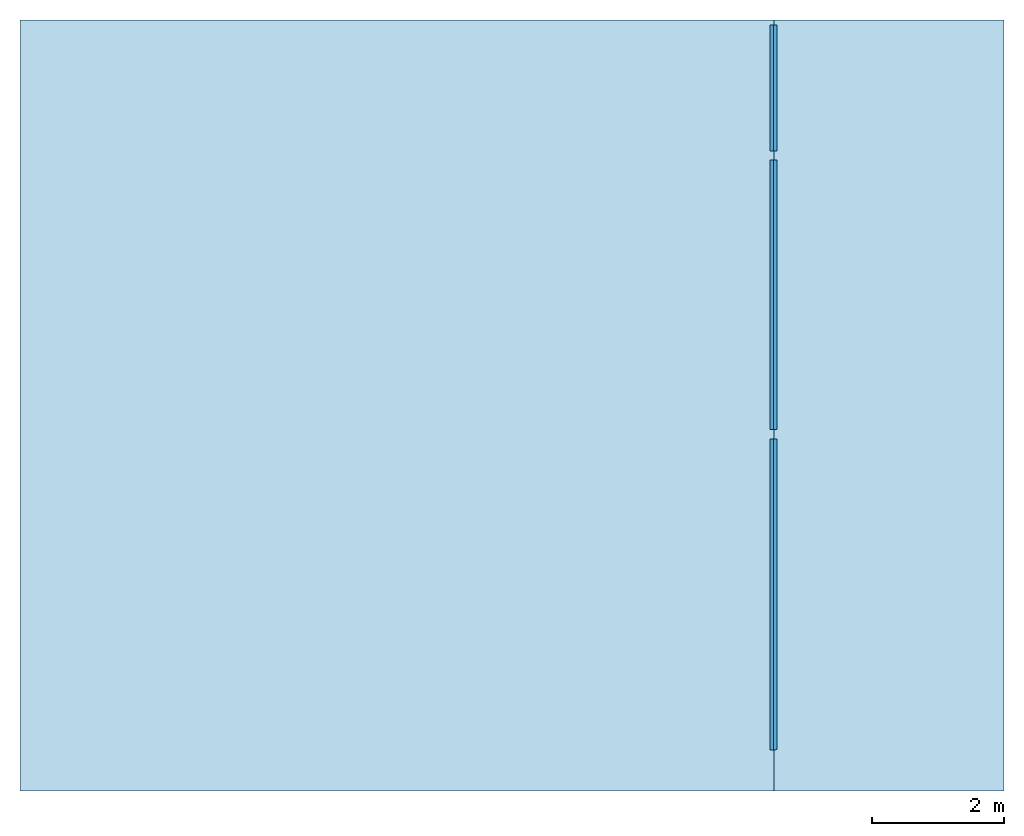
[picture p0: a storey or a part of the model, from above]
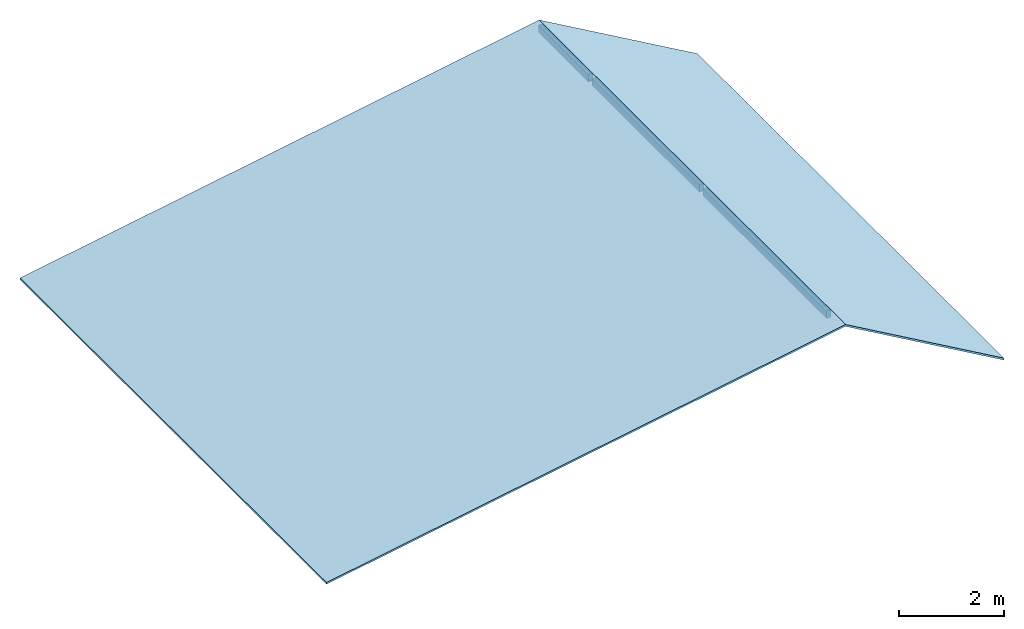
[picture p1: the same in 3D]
Properties of the parts of a building model (IFC4)

# File
Description: ViewDefinition [ReferenceView_V1.2], RevitIdentifiers [ContentGUID: e49f2b07-9c94-4ebe-8864-36e96c9eb5d3, VersionGUID: 72a1a56d-2964-4670-afea-b7860d60a0a9, NumberOfSaves: 74], CoordinateReference [CoordinateBase: Coordonnées partagées], ExchangeRequirement [Structural]
File name: 15-00625-Préfecture des Vosges-PRO-Maquette structure.ifc
Time: 2025-05-12T09:06:08+01:00
Written by: ODA SDAI 24.12
Made in: Autodesk Revit 25.3.0.46 (FRA) - IFC 25.3.0.46

# IfcProject, 15-00625
LongName: Centre d'examen des permis de conduire; Phase: PRO

# IfcSite, Default
RefLatitude: 48, 51, 23, 999633; RefLongitude: 2, 21, 3, 553905; RefElevation: 0 cm
Pset_SiteCommon - Reference: Informations sur le projet

# IfcSite: Regard drain:500 mmx500 mm (5)
Material: <Unnamed>
Pset_SiteCommon - Reference: 500 mmx500 mm
Qto_SiteBaseQuantities - GrossArea: 0.1444 m2
Name (Regard drain:500 mmx500 mm:...)
332220
340264
341394
343831
343919

# IfcBuilding
Pset_BuildingCommon - Reference: Informations sur le projet; NumberOfStoreys: 4
Pset_BuildingElementProxyCommon - Reference: Informations sur le projet; IsExternal: no
Pset_BuildingStoreyCommon - Reference: Informations sur le projet; sets with these values: 2

# IfcBuildingStorey: Niveau:Pointe 8 mm (4)
Pset_BuildingStoreyCommon - Reference: Pointe 8 mm
Name | LongName | Elevation (cm)
Fondation B.O. | Fondation B.O. | -30
± 0.000 | ± 0.000 | 31
+3.00 | +3.00 | 331
+5.25 | +5.25 | 556

# IfcBeam: Poutre - Lamellé-collé:10x10 (11)
In: Fondation B.O.
Type - PredefinedType: BEAM; Material: BM - C24
Type - Pset_BeamCommon - LoadBearing: yes
Pset_BeamCommon - Roll: 0 deg; Reference: 10x10
Pset_EnvironmentalImpactIndicators - Reference: 10x10; sets with these values: 2
Name (Poutre - Lamellé-collé:10x10:...) | IsExternal | Span (cm) | Slope (deg) | NetSurfaceArea (m2) | NetVolume (m3)
253672 | yes | 270.6 | 21.0071 | 1.02658 | 0.0251412
253712 | yes | 459.1 | 12.1585 | 1.83103 | 0.0443514
253883 | yes | 397.4 | 14.4253 | 1.54723 | 0.0376102
256367 | yes | 399.9 | 13.5747 | 1.51601 | 0.036857
257049 | no | 439.6 | 5.91429 | 1.6891 | 0.0415963
258776 | yes | 456.2 | 3.86876 | 1.62873 | 0.0397972
266792 | no | 435.4 | 5.80391 | 1.67125 | 0.0412361
267095 | no | 435.4 | 5.80421 | 1.67169 | 0.0412367
404951 | no | 455 | 2.92662 | 1.77425 | 0.0432159
405012 | no | 400.9 | 3.31704 | 1.54569 | 0.0380108
405029 | no | 403.4 | 3.40332 | 1.56152 | 0.0379228

# IfcBeam: Poutre - Lamellé-collé:10x18 (9)
Type - PredefinedType: BEAM; Material: BLC - GL24h
Type - Pset_BeamCommon - LoadBearing: yes
Pset_BeamCommon - Slope: 0 deg; Roll: 0 deg; Reference: 10x18
Pset_EnvironmentalImpactIndicators - Reference: 10x18; sets with these values: 2
Name (Poutre - Lamellé-collé:10x18:...) | In | IsExternal | Span (cm) | Length (cm) | CrossSectionArea (m2) | OuterSurfaceArea (m2) | GrossSurfaceArea (m2) | NetSurfaceArea (m2) | GrossVolume (m3) | NetVolume (m3)
247824 | Fondation B.O. | yes | 422 | 18 | 0.407954 | 1.50463 | 2.32054 | 2.32054 | 0.0734316 | 0.0734316
248245 | Fondation B.O. | yes | 190.8 | 18 | 0.1906 | 0.72216 | 1.10336 | 1.10336 | 0.034308 | 0.034308
248481 | Fondation B.O. | yes | 466.7 |  |  |  |  | 2.61039 |  | 0.082747
248585 | +5.25 | no | 422 | 407.9 | 0.0170671 | 2.16598 | 2.20012 | 2.20012 | 0.0696168 | 0.0696168
249977 | +5.25 | no | 190.8 | 190.4 | 0.0170671 | 1.01104 | 1.04517 | 1.04517 | 0.0324958 | 0.0324958
250041 | +5.25 | no | 477.4 |  |  |  |  | 2.53231 |  | 0.0802919
251778 | +3.00 | no | 1174.4 |  |  |  |  | 6.33634 |  | 0.196803
252924 | +3.00 | no | 1074.3 |  |  |  |  | 5.61702 |  | 0.165483
268881 | +3.00 | no | 1073.6 | 1073.55 | 0.0166706 | 5.73606 | 5.7694 | 5.7694 | 0.178967 | 0.178967

# IfcBeam: Poutre - Lamellé-collé:10x20 (3)
In: Fondation B.O.
Type - PredefinedType: BEAM; Material: BLC - GL24h
Type - Pset_BeamCommon - LoadBearing: yes
Pset_BeamCommon - IsExternal: no; Roll: 0 deg; Reference: 10x20; Slope: 7.63893 deg
Pset_EnvironmentalImpactIndicators - Reference: 10x20; sets with these values: 2
Qto_BeamBaseQuantities - Length: 10 cm; CrossSectionArea: 0.730739 m2; OuterSurfaceArea: 0.771668 m2; GrossSurfaceArea: 2.23315 m2; NetSurfaceArea: 2.23315 m2; GrossVolume: 0.0730739 m3; NetVolume: 0.0730739 m3
Name (Poutre - Lamellé-collé:10x20:...) | Span (cm)
270714 | 364.3
271733 | 369.4
271742 | 364.3

# IfcBeam: Poutre - Lamellé-collé:14x32 (5)
In: Fondation B.O.
Type - PredefinedType: BEAM; Material: BLC - GL24h
Type - Pset_BeamCommon - LoadBearing: yes
Pset_BeamCommon - IsExternal: yes; Roll: 0 deg; Reference: 14x32
Pset_EnvironmentalImpactIndicators - Reference: 14x32; sets with these values: 2
Qto_BeamBaseQuantities - Length: 14 cm
Name (Poutre - Lamellé-collé:14x32:...) | Span (cm) | Slope (deg) | CrossSectionArea (m2) | OuterSurfaceArea (m2) | GrossSurfaceArea (m2) | NetSurfaceArea (m2) | GrossVolume (m3) = NetVolume (m3)
238878 | 565.4 | 9.94208 | 1.78925 | 1.6687 | 5.24719 | 5.24719 | 0.250495
239277 | 391.5 | 29.8865 | 1.17434 | 1.1546 | 3.50328 | 3.50328 | 0.164407
241186 | 587.3 | 9.94208 | 1.83935 | 1.73201 | 5.41071 | 5.41071 | 0.257509
241188 | 391.5 | 29.8865 | 1.17434 | 1.15464 | 3.50332 | 3.50329 | 0.164407
241289 | 552.8 | 9.94208 | 1.7274 | 1.62076 | 5.07556 | 5.07556 | 0.241836

# IfcBeam: Poutre rectangulaire - Béton:25x25 ht. (2)
In: Fondation B.O.
Type - PredefinedType: BEAM; Material: Béton C20/25
Type - Pset_BeamCommon - LoadBearing: yes
Pset_BeamCommon - IsExternal: no; Reference: 25x25 ht.; Slope: 0 deg; Roll: 0 deg
Pset_EnvironmentalImpactIndicators - Reference: 25x25 ht.; sets with these values: 2
Qto_BeamBaseQuantities - CrossSectionArea: 0.0625 m2
Name (Poutre rectangulaire - Béton:25x25 ht.:...) | Span (cm) | Length (cm) | OuterSurfaceArea (m2) | GrossSurfaceArea (m2) = NetSurfaceArea (m2) | GrossVolume (m3) | NetVolume (m3)
209318 | 372.5 | 326 | 3.26 | 3.385 | 0.20375 | 0.20375
210656 | 567 | 520.5 | 5.205 | 5.33 | 0.325313 | 0.325312

# IfcBuildingElementPart (49)
Name | In | Material
Béton C20/25 | ± 0.000 | Béton C20/25
Isolant rigide | ± 0.000 | Isolant rigide
7 x Isolant rigide | Fondation B.O. | Isolant rigide
7 x Béton, règle sable/ciment | Fondation B.O. | Béton, règle sable/ciment
7 x Béton C20/25 | Fondation B.O. | Béton C20/25
7 x Panneau de grandes particules orientées | ± 0.000 | Panneau de grandes particules orientées
6 x Structure, couche de solives/chevrons en bois d'oeuvre | ± 0.000 | Structure, couche de solives/chevrons en bois d'oeuvre
6 x Panneau de grandes particules orientées | +3.00 | Panneau de grandes particules orientées
6 x Structure, couche de solives/chevrons en bois d'oeuvre | +3.00 | Structure, couche de solives/chevrons en bois d'oeuvre
Structure, couche de solives/chevrons en bois d'oeuvre sans isolant | ± 0.000 | Structure, couche de solives/chevrons en bois d'oeuvre sans isolant

# IfcCableCarrierFitting: Courbure de conduit en plastique rigide - Sans raccords:Raccord TPC BT (14)
In: Fondation B.O.
Type - Material: <Unnamed>
Pset_CableCarrierFittingTypeCommon - Reference: Raccord TPC BT; sets with these values: 2
Name (Courbure de conduit en plastique rigide - Sans raccords:Raccord TPC BT:...)
381655
381657
381707
381709
381749
381759
382104
386991
386993
387013
387017
388068
388160
388214

# IfcCableCarrierFitting: Courbure de conduit en plastique rigide - Sans raccords:Raccord TPC HT (8)
In: Fondation B.O.
Type - Material: <Unnamed>
Pset_CableCarrierFittingTypeCommon - Reference: Raccord TPC HT; sets with these values: 2
Name (Courbure de conduit en plastique rigide - Sans raccords:Raccord TPC HT:...)
387107
387116
387379
387580
387583
387587
387872
387955

# IfcCableCarrierSegment: Conduit sans raccords:TPC (27)
In: Fondation B.O.
Type - PredefinedType: CONDUITSEGMENT
Pset_CableCarrierSegmentTypeCommon - Reference: TPC; sets with these values: 2
Name (Conduit sans raccords:TPC:...) | Length (cm) | CrossSectionArea (m2) | OuterSurfaceArea (m2)
380641 | 52.444 | 0.00153415 | 0.0728229
380750 | 39.379 | 0.0081061 | 0.125692
381237 | 38.4565 | 0.00153415 | 0.0534
381434 | 138.306 | 0.00153415 | 0.19205
381444 | 426.716 | 0.00153415 | 0.592531
381651 | 278.016 | 0.00153415 | 0.386048
381652 | 12.4579 | 0.00153415 | 0.0172989
381662 | 140.699 | 0.00153415 | 0.195372
381697 | 38.4565 | 0.00153415 | 0.0534
381698 | 138.306 | 0.00153415 | 0.19205
381702 | 426.716 | 0.00153415 | 0.592531
381705 | 279.016 | 0.00153415 | 0.387437
381706 | 12.458 | 0.00153415 | 0.017299
381713 | 139.699 | 0.00153415 | 0.193984
381735 | 381.846 | 0.00153415 | 0.530225
381751 | 300.416 | 0.00153415 | 0.417152
381761 | 144.648 | 0.00153415 | 0.200855
382102 | 12.4539 | 0.00153415 | 0.0172933
387097 | 357.894 | 0.0081061 | 1.14235
387110 | 268.887 | 0.0081061 | 0.858251
387119 | 117.717 | 0.0081061 | 0.375738
387377 | 44.3337 | 0.0081061 | 0.141507
387577 | 39.379 | 0.0081061 | 0.125692
387578 | 357.894 | 0.0081061 | 1.14235
387582 | 268.887 | 0.0081061 | 0.858251
387585 | 117.718 | 0.0081061 | 0.375738
387586 | 44.3337 | 0.0081061 | 0.141507

# IfcColumn: Poteau - Bois d'oeuvre:140x140 (6)
In: +3.00
Type - PredefinedType: COLUMN; Material: Bois - Pin
Type - Pset_ColumnCommon - LoadBearing: yes
Qto_ColumnBaseQuantities - Length: 14 cm
Pset_ColumnCommon - IsExternal: no; Reference: 140x140
Pset_EnvironmentalImpactIndicators - Reference: 140x140; sets with these values: 2
Name (Poteau - Bois d'oeuvre:140x140:...) | CrossSectionArea (m2) | OuterSurfaceArea (m2) | GrossVolume (m3) = NetVolume (m3) | Roll (deg) | Slope (deg)
261963 | 0.15881 | 0.381196 | 0.0222334 | 0 | 51.6811
262317 | 0.137019 | 0.328329 | 0.0191826 | 180 | 41.4364
262414 | 0.0883574 | 0.222031 | 0.01237 | 0 | 47.7705
262415 | 0.134314 | 0.320122 | 0.018804 | 180 | 47.7705
272069 | 0.0883574 | 0.222031 | 0.01237 | 0 | 47.7705
272070 | 0.134314 | 0.320122 | 0.018804 | 180 | 47.7705

# IfcColumn: Poteau - Bois d'oeuvre:160x160 (3)
In: ± 0.000
Type - PredefinedType: COLUMN; Material: BM - Douglas
Type - Pset_ColumnCommon - LoadBearing: yes
Qto_ColumnBaseQuantities - Length: 223 cm; CrossSectionArea: 0.0256 m2; OuterSurfaceArea: 1.4272 m2; GrossVolume: 0.057088 m3; NetVolume: 0.057088 m3
Pset_ColumnCommon - IsExternal: no; Reference: 160x160
Pset_EnvironmentalImpactIndicators - Reference: 160x160; sets with these values: 2
Name (Poteau - Bois d'oeuvre:160x160:...)
260961
261099
261378

# IfcColumn: Poteau - Bois d'oeuvre:160x80 (44)
In: ± 0.000
Type - PredefinedType: COLUMN; Material: BM - Douglas
Type - Pset_ColumnCommon - LoadBearing: yes
Qto_ColumnBaseQuantities - CrossSectionArea: 0.0128 m2
Pset_ColumnCommon - IsExternal: no; Reference: 160x80
Pset_EnvironmentalImpactIndicators - Reference: 160x80; sets with these values: 2
Name (Poteau - Bois d'oeuvre:160x80:...) | Length (cm) | OuterSurfaceArea (m2) | GrossVolume (m3) = NetVolume (m3)
273647 | 287 | 1.3776 | 0.036736
274178 | 287 | 1.3776 | 0.036736
274246 | 287 | 1.3776 | 0.036736
274259 | 287 | 1.3776 | 0.036736
274270 | 287 | 1.3776 | 0.036736
274283 | 287 | 1.3776 | 0.036736
274353 | 287 | 1.3776 | 0.036736
274473 | 287 | 1.3776 | 0.036736
274540 | 287 | 1.3776 | 0.036736
274551 | 287 | 1.3776 | 0.036736
274562 | 287 | 1.3776 | 0.036736
274573 | 287 | 1.3776 | 0.036736
274689 | 223 | 1.0704 | 0.028544
275603 | 223 | 1.0704 | 0.028544
275672 | 223 | 1.0704 | 0.028544
275700 | 223 | 1.0704 | 0.028544
275763 | 223 | 1.0704 | 0.028544
275839 | 223 | 1.0704 | 0.028544
275853 | 223 | 1.0704 | 0.028544
275865 | 223 | 1.0704 | 0.028544
275877 | 223 | 1.0704 | 0.028544
275889 | 223 | 1.0704 | 0.028544
275901 | 223 | 1.0704 | 0.028544
275915 | 223 | 1.0704 | 0.028544
275927 | 223 | 1.0704 | 0.028544
275941 | 223 | 1.0704 | 0.028544
275967 | 223 | 1.0704 | 0.028544
275981 | 223 | 1.0704 | 0.028544
275993 | 223 | 1.0704 | 0.028544
276007 | 223 | 1.0704 | 0.028544
276019 | 223 | 1.0704 | 0.028544
276031 | 223 | 1.0704 | 0.028544
276043 | 223 | 1.0704 | 0.028544
276055 | 223 | 1.0704 | 0.028544
276069 | 223 | 1.0704 | 0.028544
276087 | 223 | 1.0704 | 0.028544
276099 | 223 | 1.0704 | 0.028544
276113 | 223 | 1.0704 | 0.028544
276125 | 223 | 1.0704 | 0.028544
276151 | 223 | 1.0704 | 0.028544
276167 | 223 | 1.0704 | 0.028544
276179 | 223 | 1.0704 | 0.028544
276191 | 223 | 1.0704 | 0.028544
276203 | 223 | 1.0704 | 0.028544

# IfcColumn: Poteau - Bois d'oeuvre:200x200 (3)
In: ± 0.000
Type - PredefinedType: COLUMN; Material: BCC - C24
Type - Pset_ColumnCommon - LoadBearing: yes
Qto_ColumnBaseQuantities - CrossSectionArea: 0.04 m2
Pset_ColumnCommon - IsExternal: no; Reference: 200x200
Pset_EnvironmentalImpactIndicators - Reference: 200x200; sets with these values: 2
Name (Poteau - Bois d'oeuvre:200x200:...) | Length (cm) | OuterSurfaceArea (m2) | GrossVolume (m3) = NetVolume (m3)
233240 | 500 | 4 | 0.2
233528 | 412 | 3.296 | 0.1648
233775 | 502 | 4.016 | 0.2008

# IfcDistributionPort (163)
Description: Flow
Name | FlowDirection | PredefinedType | SystemType
OutPort_344095_1 | SOURCE | PIPE | HEATING | Group: Alimentation hydraulique 4
Port_353893_0 | SOURCEANDSINK | PIPE | USERDEFINED | Group: EU/EV
Port_377618_3 | SOURCEANDSINK | PIPE | USERDEFINED | Group: EU/EV
Port_353893_1 | SOURCEANDSINK | PIPE | USERDEFINED | Group: EU/EV
Port_353943_1 | SOURCEANDSINK | PIPE | USERDEFINED | Group: EU/EV
Port_353961_0 | SOURCEANDSINK | PIPE | USERDEFINED | Group: EU/EV
Port_369566_1 | SOURCEANDSINK | PIPE | USERDEFINED | Group: EU/EV
Port_374734_1 | SOURCEANDSINK | PIPE | USERDEFINED | Group: EU/EV
Port_374743_1 | SOURCEANDSINK | PIPE | USERDEFINED | Group: EU/EV
Port_374736_0 | SOURCEANDSINK | PIPE | USERDEFINED | Group: EU/EV
Port_374743_2 | SOURCEANDSINK | PIPE | USERDEFINED | Group: EU/EV
Port_374736_1 | SOURCEANDSINK | PIPE | USERDEFINED | Group: EU/EV
Port_374747_1 | SOURCEANDSINK | PIPE | USERDEFINED | Group: EU/EV
Port_374738_0 | SOURCEANDSINK | PIPE | USERDEFINED | Group: EU/EV
Port_374747_2 | SOURCEANDSINK | PIPE | USERDEFINED | Group: EU/EV
Port_374738_1 | SOURCEANDSINK | PIPE | USERDEFINED | Group: EU/EV
Port_374810_2 | SOURCEANDSINK | PIPE | USERDEFINED | Group: EU/EV
Port_374751_0 | SOURCEANDSINK | PIPE | USERDEFINED | Group: EU/EV
Port_374762_0 | SOURCEANDSINK | PIPE | USERDEFINED | Group: EU/EV
Port_374764_1 | SOURCEANDSINK | PIPE | USERDEFINED | Group: EU/EV
Port_374810_3 | SOURCEANDSINK | PIPE | USERDEFINED | Group: EU/EV
Port_374770_0 | SOURCEANDSINK | PIPE | HEATING | Group: Alimentation hydraulique 10
Port_374770_1 | SOURCEANDSINK | PIPE | HEATING | Group: Alimentation hydraulique 10
Port_374810_1 | SOURCEANDSINK | PIPE | USERDEFINED | Group: EU/EV
Port_377303_1 | SOURCEANDSINK | PIPE | USERDEFINED | Group: EU/EV
Port_375601_0 | SOURCEANDSINK | PIPE | USERDEFINED | Group: EU/EV
Port_377303_0 | SOURCEANDSINK | PIPE | USERDEFINED | Group: EU/EV
Port_377611_2 | SOURCEANDSINK | PIPE | USERDEFINED | Group: EU/EV
Port_377473_0 | SOURCEANDSINK | PIPE | USERDEFINED | Group: EU/EV
Port_377618_2 | SOURCEANDSINK | PIPE | USERDEFINED | Group: EU/EV
Port_377473_1 | SOURCEANDSINK | PIPE | USERDEFINED | Group: EU/EV
Port_377644_2 | SOURCEANDSINK | PIPE | USERDEFINED | Group: EU/EV
Port_377611_1 | SOURCEANDSINK | PIPE | USERDEFINED | Group: EU/EV
Port_378065_0 | SOURCEANDSINK | PIPE | USERDEFINED | Group: EU/EV
Port_377611_3 | SOURCEANDSINK | PIPE | USERDEFINED | Group: EU/EV
Port_377619_0 | SOURCEANDSINK | PIPE | USERDEFINED | Group: EU/EV
Port_377618_1 | SOURCEANDSINK | PIPE | USERDEFINED | Group: EU/EV
Port_377619_1 | SOURCEANDSINK | PIPE | USERDEFINED | Group: EU/EV
Port_377636_0 | SOURCEANDSINK | PIPE | USERDEFINED | Group: EU/EV
Port_377644_1 | SOURCEANDSINK | PIPE | USERDEFINED | Group: EU/EV
Port_377636_1 | SOURCEANDSINK | PIPE | USERDEFINED | Group: EU/EV
Port_377665_1 | SOURCEANDSINK | PIPE | USERDEFINED | Group: EU/EV
Port_377649_1 | SOURCEANDSINK | PIPE | USERDEFINED | Group: EU/EV
Port_377665_2 | SOURCEANDSINK | PIPE | USERDEFINED | Group: EU/EV
Port_378056_0 | SOURCEANDSINK | PIPE | USERDEFINED | Group: EU/EV
Port_378301_2 | SOURCEANDSINK | PIPE | USERDEFINED | Group: EU/EV
Port_378064_1 | SOURCEANDSINK | PIPE | USERDEFINED | Group: EU/EV
Port_378546_0 | SOURCEANDSINK | PIPE | USERDEFINED | Group: EU/EV
Port_378064_2 | SOURCEANDSINK | PIPE | USERDEFINED | Group: EU/EV
Port_378065_1 | SOURCEANDSINK | PIPE | USERDEFINED | Group: EU/EV
Port_378064_3 | SOURCEANDSINK | PIPE | USERDEFINED | Group: EU/EV
Port_378302_0 | SOURCEANDSINK | PIPE | USERDEFINED | Group: EU/EV
Port_378281_1 | SOURCEANDSINK | PIPE | USERDEFINED | Group: EU/EV
Port_378301_3 | SOURCEANDSINK | PIPE | USERDEFINED | Group: EU/EV
Port_378301_1 | SOURCEANDSINK | PIPE | USERDEFINED | Group: EU/EV
Port_378302_1 | SOURCEANDSINK | PIPE | USERDEFINED | Group: EU/EV
Port_378337_1 | SOURCEANDSINK | PIPE | USERDEFINED | Group: EU/EV
Port_378545_3 | SOURCEANDSINK | PIPE | USERDEFINED | Group: EU/EV
Port_378346_0 | SOURCEANDSINK | PIPE | USERDEFINED | Group: EU/EV
Port_378545_1 | SOURCEANDSINK | PIPE | USERDEFINED | Group: EU/EV
Port_378346_1 | SOURCEANDSINK | PIPE | USERDEFINED | Group: EU/EV
Port_378545_2 | SOURCEANDSINK | PIPE | USERDEFINED | Group: EU/EV
Port_378546_1 | SOURCEANDSINK | PIPE | USERDEFINED | Group: EU/EV
Port_379876_0 | SOURCEANDSINK | PIPE | HEATING | Group: AEP
Port_379876_1 | SOURCEANDSINK | PIPE | HEATING | Group: AEP
Port_380641_0 | SOURCEANDSINK | CABLECARRIER | CONVEYING
Port_380641_1 | SOURCEANDSINK | CABLECARRIER | CONVEYING
Port_381749_1 | SOURCEANDSINK | CABLECARRIER | CONVEYING
Port_380750_0 | SOURCEANDSINK | CABLECARRIER | CONVEYING
Port_387107_1 | SOURCEANDSINK | CABLECARRIER | CONVEYING
Port_380750_1 | SOURCEANDSINK | CABLECARRIER | CONVEYING
Port_381237_0 | SOURCEANDSINK | CABLECARRIER | CONVEYING
Port_381237_1 | SOURCEANDSINK | CABLECARRIER | CONVEYING
Port_386993_2 | SOURCEANDSINK | CABLECARRIER | CONVEYING
Port_381434_0 | SOURCEANDSINK | CABLECARRIER | CONVEYING
Port_386991_1 | SOURCEANDSINK | CABLECARRIER | CONVEYING
Port_381434_1 | SOURCEANDSINK | CABLECARRIER | CONVEYING
Port_386993_1 | SOURCEANDSINK | CABLECARRIER | CONVEYING
Port_381444_0 | SOURCEANDSINK | CABLECARRIER | CONVEYING
Port_386991_2 | SOURCEANDSINK | CABLECARRIER | CONVEYING
Port_381444_1 | SOURCEANDSINK | CABLECARRIER | CONVEYING
Port_381655_2 | SOURCEANDSINK | CABLECARRIER | CONVEYING
Port_381651_0 | SOURCEANDSINK | CABLECARRIER | CONVEYING
Port_381655_1 | SOURCEANDSINK | CABLECARRIER | CONVEYING
Port_381651_1 | SOURCEANDSINK | CABLECARRIER | CONVEYING
Port_381657_1 | SOURCEANDSINK | CABLECARRIER | CONVEYING
Port_381652_0 | SOURCEANDSINK | CABLECARRIER | CONVEYING
Port_381657_2 | SOURCEANDSINK | CABLECARRIER | CONVEYING
Port_381652_1 | SOURCEANDSINK | CABLECARRIER | CONVEYING
Port_388214_1 | SOURCEANDSINK | CABLECARRIER | CONVEYING
Port_381662_0 | SOURCEANDSINK | CABLECARRIER | CONVEYING
Port_388214_2 | SOURCEANDSINK | CABLECARRIER | CONVEYING
Port_381662_1 | SOURCEANDSINK | CABLECARRIER | CONVEYING
Port_381697_0 | SOURCEANDSINK | CABLECARRIER | CONVEYING
Port_381697_1 | SOURCEANDSINK | CABLECARRIER | CONVEYING
Port_387017_2 | SOURCEANDSINK | CABLECARRIER | CONVEYING
Port_381698_0 | SOURCEANDSINK | CABLECARRIER | CONVEYING
Port_387013_1 | SOURCEANDSINK | CABLECARRIER | CONVEYING
Port_381698_1 | SOURCEANDSINK | CABLECARRIER | CONVEYING
Port_387017_1 | SOURCEANDSINK | CABLECARRIER | CONVEYING
Port_381702_0 | SOURCEANDSINK | CABLECARRIER | CONVEYING
Port_387013_2 | SOURCEANDSINK | CABLECARRIER | CONVEYING
Port_381702_1 | SOURCEANDSINK | CABLECARRIER | CONVEYING
Port_381707_2 | SOURCEANDSINK | CABLECARRIER | CONVEYING
Port_381705_0 | SOURCEANDSINK | CABLECARRIER | CONVEYING
Port_381707_1 | SOURCEANDSINK | CABLECARRIER | CONVEYING
Port_381705_1 | SOURCEANDSINK | CABLECARRIER | CONVEYING
Port_381709_1 | SOURCEANDSINK | CABLECARRIER | CONVEYING
Port_381706_0 | SOURCEANDSINK | CABLECARRIER | CONVEYING
Port_381709_2 | SOURCEANDSINK | CABLECARRIER | CONVEYING
Port_381706_1 | SOURCEANDSINK | CABLECARRIER | CONVEYING
Port_388160_1 | SOURCEANDSINK | CABLECARRIER | CONVEYING
Port_381713_0 | SOURCEANDSINK | CABLECARRIER | CONVEYING
Port_388160_2 | SOURCEANDSINK | CABLECARRIER | CONVEYING
Port_381713_1 | SOURCEANDSINK | CABLECARRIER | CONVEYING
Port_381735_0 | SOURCEANDSINK | CABLECARRIER | CONVEYING
Port_381749_2 | SOURCEANDSINK | CABLECARRIER | CONVEYING
Port_381735_1 | SOURCEANDSINK | CABLECARRIER | CONVEYING
Port_381759_2 | SOURCEANDSINK | CABLECARRIER | CONVEYING
Port_381751_0 | SOURCEANDSINK | CABLECARRIER | CONVEYING
Port_381759_1 | SOURCEANDSINK | CABLECARRIER | CONVEYING
Port_381751_1 | SOURCEANDSINK | CABLECARRIER | CONVEYING
Port_382104_1 | SOURCEANDSINK | CABLECARRIER | CONVEYING
Port_381761_0 | SOURCEANDSINK | CABLECARRIER | CONVEYING
Port_388068_2 | SOURCEANDSINK | CABLECARRIER | CONVEYING
Port_381761_1 | SOURCEANDSINK | CABLECARRIER | CONVEYING
Port_382102_0 | SOURCEANDSINK | CABLECARRIER | CONVEYING
Port_382104_2 | SOURCEANDSINK | CABLECARRIER | CONVEYING
Port_382102_1 | SOURCEANDSINK | CABLECARRIER | CONVEYING
Port_388068_1 | SOURCEANDSINK | CABLECARRIER | CONVEYING
Port_387097_0 | SOURCEANDSINK | CABLECARRIER | CONVEYING
Port_387107_2 | SOURCEANDSINK | CABLECARRIER | CONVEYING
Port_387097_1 | SOURCEANDSINK | CABLECARRIER | CONVEYING
Port_387116_2 | SOURCEANDSINK | CABLECARRIER | CONVEYING
Port_387110_0 | SOURCEANDSINK | CABLECARRIER | CONVEYING
Port_387116_1 | SOURCEANDSINK | CABLECARRIER | CONVEYING
Port_387110_1 | SOURCEANDSINK | CABLECARRIER | CONVEYING
Port_387379_1 | SOURCEANDSINK | CABLECARRIER | CONVEYING
Port_387119_0 | SOURCEANDSINK | CABLECARRIER | CONVEYING
Port_387955_2 | SOURCEANDSINK | CABLECARRIER | CONVEYING
Port_387119_1 | SOURCEANDSINK | CABLECARRIER | CONVEYING
Port_387377_0 | SOURCEANDSINK | CABLECARRIER | CONVEYING
Port_387379_2 | SOURCEANDSINK | CABLECARRIER | CONVEYING
Port_387377_1 | SOURCEANDSINK | CABLECARRIER | CONVEYING
Port_387955_1 | SOURCEANDSINK | CABLECARRIER | CONVEYING
Port_387577_0 | SOURCEANDSINK | CABLECARRIER | CONVEYING
Port_387580_1 | SOURCEANDSINK | CABLECARRIER | CONVEYING
Port_387577_1 | SOURCEANDSINK | CABLECARRIER | CONVEYING
Port_387578_0 | SOURCEANDSINK | CABLECARRIER | CONVEYING
Port_387580_2 | SOURCEANDSINK | CABLECARRIER | CONVEYING
Port_387578_1 | SOURCEANDSINK | CABLECARRIER | CONVEYING
Port_387583_2 | SOURCEANDSINK | CABLECARRIER | CONVEYING
Port_387582_0 | SOURCEANDSINK | CABLECARRIER | CONVEYING
Port_387583_1 | SOURCEANDSINK | CABLECARRIER | CONVEYING
Port_387582_1 | SOURCEANDSINK | CABLECARRIER | CONVEYING
Port_387587_1 | SOURCEANDSINK | CABLECARRIER | CONVEYING
Port_387585_0 | SOURCEANDSINK | CABLECARRIER | CONVEYING
Port_387872_2 | SOURCEANDSINK | CABLECARRIER | CONVEYING
Port_387585_1 | SOURCEANDSINK | CABLECARRIER | CONVEYING
Port_387586_0 | SOURCEANDSINK | CABLECARRIER | CONVEYING
Port_387587_2 | SOURCEANDSINK | CABLECARRIER | CONVEYING
Port_387586_1 | SOURCEANDSINK | CABLECARRIER | CONVEYING
Port_387872_1 | SOURCEANDSINK | CABLECARRIER | CONVEYING

# IfcDistributionSystem: Alimentation hydraulique (3)
PredefinedType: HEATING
Pset_DistributionSystemCommon - Reference: Alimentation hydraulique
Name
Alimentation hydraulique 4
Alimentation hydraulique 10
AEP

# IfcDistributionSystem: Autre, EU/EV
PredefinedType: USERDEFINED
Pset_DistributionSystemCommon - Reference: Autre

# IfcFooting: Semelle filante:SF 50x25 ht. (6)
In: Fondation B.O.
Type - PredefinedType: STRIP_FOOTING
Material: Béton C20/25
Pset_EnvironmentalImpactIndicators - Reference: SF 50x25 ht.; sets with these values: 4
Qto_FootingBaseQuantities - Length: 25 cm
Name (Semelle filante:SF 50x25 ht.:...) | CrossSectionArea (m2) | OuterSurfaceArea (m2) | GrossSurfaceArea (m2) | GrossVolume (m3) | NetVolume (m3)
198844 | 1.375 | 1.625 | 4.375 | 0.34375 | 0.74625 | Qto_FootingBaseQuantities - Width: 275 cm; Height: 50 cm
206181 | 0.60775 | 0.9575 | 2.173 | 0.151937 | 0.898187 | Qto_FootingBaseQuantities - Width: 322 cm; Height: 50 cm
208354 | 1.882 | 2.17 | 5.934 | 0.4705 | 0.4705
208367 | 5.2325 | 5.4825 | 15.9475 | 1.30812 | 1.30812 | Qto_FootingBaseQuantities - Width: 1046.5 cm; Height: 50 cm
209443 | 1.0025 | 1.455 | 3.46 | 0.250625 | 0.250625
209463 | 0.9525 | 1.405 | 3.31 | 0.238125 | 0.238125

# IfcFooting: Semelle filante:SF 50x25 ht. 2 (7)
In: Fondation B.O.
Type - PredefinedType: STRIP_FOOTING
Material: Béton C20/25
Pset_EnvironmentalImpactIndicators - Reference: SF 50x25 ht. 2; sets with these values: 4
Qto_FootingBaseQuantities - Length: 25 cm
Name (Semelle filante:SF 50x25 ht. 2:...) | Width (cm) | Height (cm) | CrossSectionArea (m2) | OuterSurfaceArea (m2) | GrossSurfaceArea (m2) | GrossVolume (m3) = NetVolume (m3)
198193 | 820 | 50 | 4.1 | 4.35 | 12.55 | 1.025
198208 | 492 | 50 | 2.46 | 2.71 | 7.63 | 0.615
198218 | 363 | 50 | 1.815 | 2.065 | 5.695 | 0.45375
198232 | 163 | 50 | 0.815 | 1.065 | 2.695 | 0.20375
198249 | 960 | 50 | 4.8 | 5.05 | 14.65 | 1.2
198259 | 1399 | 50 | 6.995 | 7.245 | 21.235 | 1.74875
223356 |  |  | 2.58225 | 2.875 | 8.0395 | 0.645563

# IfcMember: Poutre - Lamellé-collé:10x10 (3)
In: Fondation B.O.
Type - PredefinedType: BRACE; Material: BM - C24
Type - Pset_MemberCommon - LoadBearing: yes
Pset_EnvironmentalImpactIndicators - Reference: 10x10
Pset_MemberCommon - Roll: 0 deg; Reference: 10x10
Name (Poutre - Lamellé-collé:10x10:...) | IsExternal | Span (cm) | Slope (deg) | NetSurfaceArea (m2) | NetVolume (m3)
257361 | yes | 400.8 | 4.69304 | 1.41485 | 0.0345599
257390 | yes | 396 | 4.49575 | 1.53956 | 0.0379342
272898 | no | 252.1 | 5.28221 | 0.960764 | 0.0231489

# IfcMember: Poutre - Lamellé-collé:10x18 (16)
In: Fondation B.O.
Type - PredefinedType: PURLIN; Material: BLC - GL24h
Type - Pset_MemberCommon - LoadBearing: yes
Pset_EnvironmentalImpactIndicators - Reference: 10x18
Pset_MemberCommon - Slope: 0 deg; Roll: 0 deg; Reference: 10x18
Name (Poutre - Lamellé-collé:10x18:...) | IsExternal | Span (cm) | Length (cm) | CrossSectionArea (m2) | OuterSurfaceArea (m2) | GrossSurfaceArea (m2) | NetSurfaceArea (m2) | GrossVolume (m3) | NetVolume (m3)
249195 | yes | 422 | 18 | 0.408 | 1.5048 | 2.3208 | 2.3208 | 0.07344 | 0.07344
249285 | yes | 422 | 18 | 0.408 | 1.5048 | 2.3208 | 2.3208 | 0.07344 | 0.07344
249292 | yes | 620.7 | 18 | 0.631394 | 2.30902 | 3.5718 | 3.5718 | 0.113651 | 0.113651
249740 | yes | 190.8 | 18 | 0.1904 | 0.72144 | 1.10224 | 1.10224 | 0.034272 | 0.034272
249853 | yes | 494.5 |  |  |  |  | 2.76816 |  | 0.0878181
249854 | yes | 511.5 |  |  |  |  | 2.86319 |  | 0.0908726
249855 | yes | 528.6 |  |  |  |  | 2.95901 |  | 0.0939526
250751 | yes | 620.7 | 18 | 0.6137 | 2.24532 | 3.47272 | 3.47272 | 0.110466 | 0.110466
251517 | yes | 190.8 | 18 | 0.1904 | 0.72144 | 1.10224 | 1.10224 | 0.034272 | 0.034272
251607 | yes | 541.2 |  |  |  |  | 3.02984 |  | 0.0962293
272228 | no | 181.9 | 18 | 0.183427 | 0.696338 | 1.06319 | 1.06319 | 0.0330169 | 0.0330169
306267 | no | 181.8 | 18 | 0.18345 | 0.69642 | 1.06332 | 1.06332 | 0.033021 | 0.033021
403328 | no | 420 | 18 | 0.409932 | 1.51175 | 2.33162 | 2.33162 | 0.0737877 | 0.0737877
403339 | no | 465.1 | 18 | 0.4601 | 1.69236 | 2.61256 | 2.61256 | 0.082818 | 0.082818
404074 | no | 420 | 18 | 0.41 | 1.512 | 2.332 | 2.332 | 0.0738 | 0.0738
404186 | no | 465.1 | 18 | 0.460017 | 1.69206 | 2.6121 | 2.6121 | 0.0828031 | 0.0828031

# IfcOpeningElement (3)
In: ± 0.000
PredefinedType: OPENING
Qto_OpeningElementBaseQuantities - Depth: 304.8 cm; Height: 222 cm; Width: 102 cm
Name (Mur de base:Relevé 15 cm:...)
196332
196387
196490

# IfcPipeFitting: Plumbing-Bend-Valsir-PP-Negative-02:Standard (4)
In: Fondation B.O.
Type - Material: RAL 7037
Type - Pset_ManufacturerTypeInformation - Manufacturer: Valsir S.p.A.
Pset_EnvironmentalImpactIndicators - Reference: Standard; sets with these values: 2
Group: EU/EV
Name (Plumbing-Bend-Valsir-PP-Negative-02:Standard:...)
374743
374747
377644
377665

# IfcPipeFitting: Plumbing-Branch-Valsir-PP-02:Standard (6)
In: Fondation B.O.
Type - Material: RAL 7037
Type - Pset_ManufacturerTypeInformation - Manufacturer: Valsir S.p.A.
Pset_EnvironmentalImpactIndicators - Reference: Standard; sets with these values: 2
Group: EU/EV
Name (Plumbing-Branch-Valsir-PP-02:Standard:...)
374810
377611
377618
378064
378301
378545

# IfcPipeFitting: ^DON'T_USE^Plumbing-Bend-Valsir-PP-Positive-02_ForDouble45Bend:Standard (12)
In: Fondation B.O.
Type - Material: RAL 7037
Type - Pset_ManufacturerTypeInformation - Manufacturer: Valsir S.p.A.
Pset_EnvironmentalImpactIndicators - Reference: Standard; sets with these values: 2
Name (^DON'T_USE^Plumbing-Bend-Valsir-PP-Positive-02_ForDouble45Bend:Standard:...)
375411
375413
375515
375517
377830
377832
378252
378254
378314
378316
378557
378559

# IfcPipeSegment: Canalisation souple arrondie:PEHD, Canalisation souple arrondie:PEHD:379876
In: Fondation B.O.
Type - PredefinedType: FLEXIBLESEGMENT
Pset_EnvironmentalImpactIndicators - Reference: PEHD; sets with these values: 2
Group: AEP

# IfcPipeSegment: Canalisation:Drain enrobé (5)
In: Fondation B.O.
Pset_EnvironmentalImpactIndicators - Reference: Drain enrobé; sets with these values: 2
Qto_PipeSegmentBaseQuantities - GrossCrossSectionArea: 0.0102593 m2; NetCrossSectionArea: 0.0102593 m2
Name (Canalisation:Drain enrobé:...) | Length (cm) | OuterSurfaceArea (m2)
341244 | 975 | 3.50107
343793 | 1796.5 | 6.45094
344029 | 1024.5 | 3.67882
344061 | 1855.5 | 6.6628
344095 | 100 | 0.359084 | Group: Alimentation hydraulique 4

# IfcPipeSegment: Canalisation:Valsir PP3 (24)
In: Fondation B.O.
Type - Pset_ManufacturerTypeInformation - Manufacturer: Valsir S.p.A.
Pset_EnvironmentalImpactIndicators - Reference: Valsir PP3; sets with these values: 2
Qto_PipeSegmentBaseQuantities - GrossCrossSectionArea: 0.00950189 m2; NetCrossSectionArea: 0.00950189 m2
Name (Canalisation:Valsir PP3:...) | Length (cm) | OuterSurfaceArea (m2) | Group
353893 | 101.827 | 0.351888 | EU/EV
353943 | 95.3738 | 0.329588 | EU/EV
353961 | 48.8721 | 0.16889 | EU/EV
369566 | 88.144 | 0.304604 | EU/EV
374734 | 7.5888 | 0.026225 | EU/EV
374736 | 289.345 | 0.999905 | EU/EV
374738 | 237.158 | 0.819558 | EU/EV
374751 | 96.6627 | 0.334042 | EU/EV
374762 | 93.6453 | 0.323615 | EU/EV
374764 | 162.488 | 0.561519 | EU/EV
374770 | 94.6895 | 0.327224 | Alimentation hydraulique 10
375601 | 91.4242 | 0.315939 | EU/EV
377303 | 30.6884 | 0.106051 | EU/EV
377473 | 49.7103 | 0.171786 | EU/EV
377619 | 171.107 | 0.591305 | EU/EV
377636 | 143.956 | 0.497476 | EU/EV
377649 | 110.295 | 0.381151 | EU/EV
378056 | 107.784 | 0.372474 | EU/EV
378065 | 27.0526 | 0.0934871 | EU/EV
378281 | 60.0539 | 0.207531 | EU/EV
378302 | 38.1827 | 0.13195 | EU/EV
378337 | 36.7693 | 0.127066 | EU/EV
378346 | 389.836 | 1.34718 | EU/EV
378546 | 51.2289 | 0.177034 | EU/EV

# IfcRoof: Toit de base:Bac Acier 3.333.39 T, Toit de base:Bac Acier 3.333.39 T:262438
In: +3.00
Pset_EnvironmentalImpactIndicators - Reference: Bac Acier 3.333.39 T
Pset_RoofCommon - IsExternal: yes; Reference: Bac Acier 3.333.39 T
Qto_RoofBaseQuantities - GrossArea: 43.7491 m2; NetArea: 43.7491 m2; ProjectedArea: 43.3609 m2

# IfcRoof: Toit de base:Bac Acier 3.333.39 T, Toit de base:Bac Acier 3.333.39 T:234167
In: +5.25
Type - Pset_RoofCommon - ThermalTransmittance: 415.385 kg/K/s3
Material: Panneau métallique
Pset_EnvironmentalImpactIndicators - Reference: Bac Acier 3.333.39 T
Pset_RoofCommon - IsExternal: yes; Reference: Bac Acier 3.333.39 T
Qto_RoofBaseQuantities - GrossArea: 182.037 m2; NetArea: 182.037 m2; ProjectedArea: 173.766 m2

# IfcSlab: Gros béton:Gros béton, Gros béton:Gros béton:318225
In: Fondation B.O.
Type - PredefinedType: BASESLAB
Pset_EnvironmentalImpactIndicators - Reference: Gros béton; sets with these values: 2
Pset_SlabCommon - IsExternal: no; Reference: Gros béton
Qto_SlabBaseQuantities - Width: 322 cm; Length: 50 cm; Depth: 10 cm; Perimeter: 744 cm; GrossArea: 1.61 m2; NetArea: 39.2145 m2; GrossVolume: 0.161 m3; NetVolume: 3.92145 m3

# IfcSlab: Semelle Isolée + GB:100x100x30 ht. (4)
In: Fondation B.O.
Type - PredefinedType: BASESLAB; Material: Par défaut
Pset_EnvironmentalImpactIndicators - Reference: 100x100x30 ht.; sets with these values: 2
Pset_SlabCommon - IsExternal: no; Reference: 100x100x30 ht.
Qto_SlabBaseQuantities - Width: 100 cm; Length: 100 cm; Perimeter: 400 cm; GrossArea: 1 m2; NetArea: 2 m2; NetVolume: 0.35 m3
Name (Semelle Isolée + GB:100x100x30 ht.:...) | Depth (cm) | GrossVolume (m3)
206858 | 30 | 0.3
207169 | 5 | 0.05 | Pset_SlabCommon - PitchAngle: 0 deg
207300 | 5 | 0.05 | Pset_SlabCommon - PitchAngle: 0 deg
207585 | 30 | 0.3

# IfcSlab: Sol:Dalle béton 20 cm, Sol:Dalle béton 20 cm:196768
In: ± 0.000
Type - PredefinedType: FLOOR
Type - Pset_SlabCommon - ThermalTransmittance: 0.175 kg/K/s3
Pset_EnvironmentalImpactIndicators - Reference: Dalle béton 20 cm; sets with these values: 2
Pset_SlabCommon - LoadBearing: yes; Reference: Dalle béton 20 cm; PitchAngle: 0 deg; IsExternal: no
Qto_SlabBaseQuantities - Béton C20/25, Width: 20 cm; Isolant rigide, Width: 20 cm; Width: 40 cm; GrossArea: 133.303 m2; NetArea: 133.303 m2; NetVolume: 53.3212 m3

# IfcSlab: Toit de base:Bac Acier 3.333.39 T, Toit de base:Bac Acier 3.333.39 T:262438
In: +3.00
Type - Pset_RoofCommon - ThermalTransmittance: 415.385 kg/K/s3
PredefinedType: ROOF; Material: Panneau métallique
Pset_EnvironmentalImpactIndicators - Reference: Bac Acier 3.333.39 T; sets with these values: 2
Pset_SlabCommon - IsExternal: yes; Reference: Bac Acier 3.333.39 T; PitchAngle: 7.63893 deg
Qto_SlabBaseQuantities - NetArea: 4.06443 m2; NetVolume: 0.158513 m2; GrossArea: 43.7491 m2; GrossVolume: 0.158513 m2; Length: 3.9 cm; Perimeter: 3083.77 cm

# IfcWall: Mur de base:MOB - 145+12 mm (12)
Type - PredefinedType: STANDARD
Type - Pset_WallCommon - ThermalTransmittance: 0.169492 kg/K/s3
Pset_EnvironmentalImpactIndicators - Reference: MOB - 145+12 mm; sets with these values: 2
Pset_WallCommon - IsExternal: yes; LoadBearing: yes; Reference: MOB - 145+12 mm
Name (Mur de base:MOB - 145+12 mm:...) | In | ExtendToStructure | Length (cm) | NetVolume (m3)
228137 | ± 0.000 | no | 893.7 | 3.4645
228414 | ± 0.000 | no | 190 | 0.850155
228561 | ± 0.000 | no | 561 | 2.18191
228720 | ± 0.000 | no | 775.7 | 3.08465
228940 | ± 0.000 | no | 1454.7 | 4.49475
229113 | ± 0.000 | no | 965.7 | 3.92249
235645 | +3.00 | yes | 775.7 | 0.159568
235821 | +3.00 | yes | 1454.7 | 2.79822
236007 | +3.00 | yes | 965.7 | 0.306464
236276 | +3.00 | yes | 893.7 | 2.17487
236447 | +3.00 | yes | 190 | 0.334898
236660 | +3.00 | yes | 561 | 0.654611

# IfcWall: Mur de base:MOB - 145+12 mm sans isolant, Mur de base:MOB - 145+12 mm sans isolant:259256
In: ± 0.000
Type - PredefinedType: STANDARD
Type - Pset_WallCommon - ThermalTransmittance: 0.169492 kg/K/s3
Pset_EnvironmentalImpactIndicators - Reference: MOB - 145+12 mm sans isolant; sets with these values: 2
Pset_WallCommon - IsExternal: yes; LoadBearing: yes; ExtendToStructure: no; Reference: MOB - 145+12 mm sans isolant
Qto_WallBaseQuantities - Length: 366.5 cm; NetVolume: 1.53779 m3

# IfcWall: Mur de base:Relevé 15 cm (6)
In: ± 0.000
Type - PredefinedType: STANDARD
Material: Béton C20/25
Pset_EnvironmentalImpactIndicators - Reference: Relevé 15 cm; sets with these values: 2
Pset_WallCommon - Reference: Relevé 15 cm; IsExternal: yes; LoadBearing: yes; ExtendToStructure: no
Name (Mur de base:Relevé 15 cm:...) | Length (cm) | NetVolume (m3) | Height (cm) | Width (cm) | GrossFootprintArea (m2) | GrossVolume (m3) | GrossSideArea (m2) = NetSideArea (m2)
196168 | 777 | 0.167025
196264 | 1456 | 0.23307
196332 | 980 | 0.220065 | 17 | 15 | 1.4475 | 0.22389 | 1.4926
196387 | 908 | 0.203618 | 17 | 15 | 1.35075 | 0.20553 | 1.3702
196424 | 190 | 0.04845 | 17 | 15 | 0.285 | 0.04845 | 0.323
196490 | 561 | 0.115133 | 17 | 15 | 0.83025 | 0.117045 | 0.7803

# IfcWall: Mur de base:Soubassement 15 cm (4)
In: Fondation B.O.
Type - PredefinedType: STANDARD
Material: Béton C20/25
Qto_WallBaseQuantities - Height: 76 cm; Width: 15 cm
Pset_EnvironmentalImpactIndicators - Reference: Soubassement 15 cm; sets with these values: 2
Pset_WallCommon - IsExternal: yes; LoadBearing: yes; ExtendToStructure: no; Reference: Soubassement 15 cm
Name (Mur de base:Soubassement 15 cm:...) | Length (cm) | GrossFootprintArea (m2) | GrossVolume (m3) = NetVolume (m3) | GrossSideArea (m2) = NetSideArea (m2)
202252 | 1063 | 1.5945 | 1.21182 | 8.0788
202430 | 158 | 0.237 | 0.18012 | 1.2008
202738 | 168 | 0.252 | 0.19152 | 1.2768
208196 | 351.5 | 0.52725 | 0.40071 | 2.6714

# IfcWall: Mur de base:Soubassement 20 cm (2)
In: Fondation B.O.
Type - PredefinedType: STANDARD
Material: Béton C20/25
Qto_WallBaseQuantities - Height: 19 cm; Width: 20 cm
Pset_EnvironmentalImpactIndicators - Reference: Soubassement 20 cm; sets with these values: 2
Pset_WallCommon - IsExternal: yes; LoadBearing: yes; Reference: Soubassement 20 cm
Name (Mur de base:Soubassement 20 cm:...) | Length (cm) | GrossFootprintArea (m2) | GrossVolume (m3) = NetVolume (m3) | GrossSideArea (m2) = NetSideArea (m2) | ExtendToStructure
198479 | 750 | 1.5 | 0.285 | 1.425 | no
206180 | 940 | 1.88 | 0.3572 | 1.786 | yes

# IfcWall: Mur de base:Soubassement 20 cm + Isolant (7)
In: Fondation B.O.
Type - PredefinedType: STANDARD
Type - Pset_WallCommon - ThermalTransmittance: 0.580098 kg/K/s3
Pset_EnvironmentalImpactIndicators - Reference: Soubassement 20 cm + Isolant; sets with these values: 2
Pset_WallCommon - IsExternal: yes; LoadBearing: yes; ExtendToStructure: no; Reference: Soubassement 20 cm + Isolant
Name (Mur de base:Soubassement 20 cm + Isolant:...) | Length (cm) | NetVolume (m3)
197020 | 777 | 0.702324
197409 | 1456 | 1.27159
197632 | 967 | 0.877746
197748 | 331.5 | 0.306318
197813 | 190 | 0.17328
197925 | 561 | 0.499494
222861 | 563.5 | 0.505764
